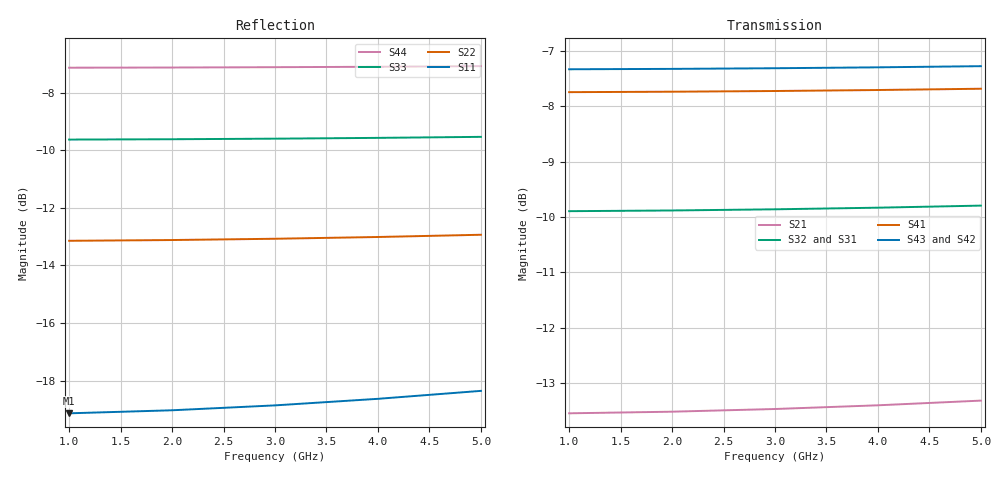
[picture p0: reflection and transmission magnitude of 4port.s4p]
! Interconnect Studio fixture, 4-port: S[r][c] = (10r + c)/100 + j(k+1)/100, k = point index
! Touchstone 1.x order: row-major, one matrix row per line
# GHz S RI R 50
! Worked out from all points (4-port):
!   5 points, 1 GHz to 5 GHz, reference 50 ohm
!   strongest paths, dB at 1 GHz, 2 GHz, 3 GHz, 4 GHz, 5 GHz:
!     S43: -7.3, -7.3, -7.3, -7.3, -7.3
!     S42: -7.5, -7.5, -7.5, -7.5, -7.5
!     S41: -7.7, -7.7, -7.7, -7.7, -7.7
!     S32: -9.9, -9.9, -9.9, -9.8, -9.8
!     S31: -10.2, -10.2, -10.1, -10.1, -10.1
!     S21: -13.5, -13.5, -13.5, -13.4, -13.3
!   lowest |S11| = -19.1 dB at 1 GHz (marker M1), VSWR 1.25, Z = 62.3 + j1.26 ohm
!   |S11| at or under -10 dB: start of sweep to end of sweep
1  0.11 0.01  0.12 0.01  0.13 0.01  0.14 0.01
   0.21 0.01  0.22 0.01  0.23 0.01  0.24 0.01
   0.31 0.01  0.32 0.01  0.33 0.01  0.34 0.01
   0.41 0.01  0.42 0.01  0.43 0.01  0.44 0.01
2  0.11 0.02  0.12 0.02  0.13 0.02  0.14 0.02
   0.21 0.02  0.22 0.02  0.23 0.02  0.24 0.02
   0.31 0.02  0.32 0.02  0.33 0.02  0.34 0.02
   0.41 0.02  0.42 0.02  0.43 0.02  0.44 0.02
3  0.11 0.03  0.12 0.03  0.13 0.03  0.14 0.03
   0.21 0.03  0.22 0.03  0.23 0.03  0.24 0.03
   0.31 0.03  0.32 0.03  0.33 0.03  0.34 0.03
   0.41 0.03  0.42 0.03  0.43 0.03  0.44 0.03
4  0.11 0.04  0.12 0.04  0.13 0.04  0.14 0.04
   0.21 0.04  0.22 0.04  0.23 0.04  0.24 0.04
   0.31 0.04  0.32 0.04  0.33 0.04  0.34 0.04
   0.41 0.04  0.42 0.04  0.43 0.04  0.44 0.04
5  0.11 0.05  0.12 0.05  0.13 0.05  0.14 0.05
   0.21 0.05  0.22 0.05  0.23 0.05  0.24 0.05
   0.31 0.05  0.32 0.05  0.33 0.05  0.34 0.05
   0.41 0.05  0.42 0.05  0.43 0.05  0.44 0.05
